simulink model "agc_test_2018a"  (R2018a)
settings: Solver=ode4  StartTime=0.0  StopTime=24  FixedStep=0.01  RelTol=1e-3

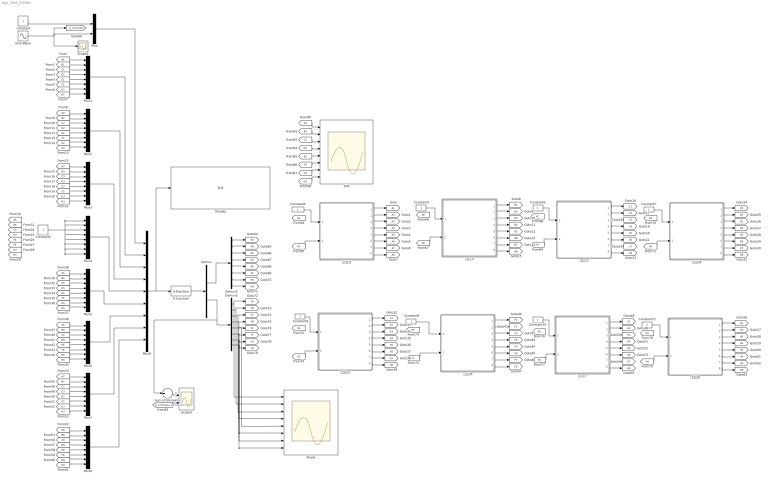
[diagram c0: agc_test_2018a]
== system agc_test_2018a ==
  Constant{,2,4..11} (10 alike) : Constant
  Demux : Demux  Outputs=2
  Demux1 : Demux  Outputs=8
  Demux2 : Demux  Outputs=8
  Display : Display
  Mux : Mux  Inputs=2
  Mux{1..8} (8 alike) : Mux  Inputs=8
  Mux9 : Mux  Inputs=9
  Power : Scope  NumInputPorts=8
  S-Function : S-Function  FunctionName=modbusCom1  SFunctionDeploymentMode=off  EnableBusSupport=off
  SOC : Scope  NumInputPorts=8
  Scope2 : Scope
  Scope3 : Scope  NumInputPorts=2
  Sine Wave : Sin  Amplitude=10000  Frequency=2*pi/8  SampleTime=0
  Sum of Elements : Sum  Inputs=+
  储能电池1 : Subsystem
  储能电池2 : Subsystem
  储能电池3 : Subsystem
  储能电池4 : Subsystem
  储能电池5 : Subsystem
  储能电池6 : Subsystem
  储能电池7 : Subsystem
  储能电池8 : Subsystem
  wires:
  Constant/1 -> Mux/1
  储能电池1/1(充放电总里程) -> [A1]
  储能电池1/2(SOC) -> [A2]
  储能电池1/3(实际功率) -> [A3]
  储能电池1/4(工作状态) -> [A4]
  储能电池1/5(额定里程) -> [A5]
  储能电池1/6(额定容量) -> [A6]
  储能电池1/7(最大充电功率) -> [A7]
  储能电池1/8(最大放电功率) -> [A8]
  储能电池2/8(最大放电功率) -> [B8]
  储能电池2/4(工作状态) -> [B4]
  储能电池2/3(实际功率) -> [B3]
  储能电池2/6(额定容量) -> [B6]
  储能电池2/1(充放电总里程) -> [B1]
  储能电池2/5(额定里程) -> [B5]
  储能电池2/2(SOC) -> [B2]
  储能电池2/7(最大充电功率) -> [B7]
  储能电池3/8(最大放电功率) -> [C8]
  储能电池3/4(工作状态) -> [C4]
  储能电池3/3(实际功率) -> [C3]
  储能电池3/6(额定容量) -> [C6]
  储能电池3/1(充放电总里程) -> [C1]
  储能电池3/5(额定里程) -> [C5]
  储能电池3/2(SOC) -> [C2]
  储能电池3/7(最大充电功率) -> [C7]
  储能电池4/8(最大放电功率) -> [D8]
  储能电池4/4(工作状态) -> [D4]
  储能电池4/3(实际功率) -> [D3]
  储能电池4/6(额定容量) -> [D6]
  储能电池4/1(充放电总里程) -> [D1]
  储能电池4/5(额定里程) -> [D5]
  储能电池4/2(SOC) -> [D2]
  储能电池4/7(最大充电功率) -> [D7]
  储能电池5/8(最大放电功率) -> [E8]
  储能电池5/4(工作状态) -> [E4]
  储能电池5/3(实际功率) -> [E3]
  储能电池5/6(额定容量) -> [E6]
  储能电池5/1(充放电总里程) -> [E1]
  储能电池5/5(额定里程) -> [E5]
  储能电池5/2(SOC) -> [E2]
  储能电池5/7(最大充电功率) -> [E7]
  储能电池6/8(最大放电功率) -> [F8]
  储能电池6/4(工作状态) -> [F4]
  储能电池6/3(实际功率) -> [F3]
  储能电池6/6(额定容量) -> [F6]
  储能电池6/1(充放电总里程) -> [F1]
  储能电池6/5(额定里程) -> [F5]
  储能电池6/2(SOC) -> [F2]
  储能电池6/7(最大充电功率) -> [F7]
  储能电池7/8(最大放电功率) -> [G8]
  储能电池7/4(工作状态) -> [G4]
  储能电池7/3(实际功率) -> [G3]
  储能电池7/6(额定容量) -> [G6]
  储能电池7/1(充放电总里程) -> [G1]
  储能电池7/5(额定里程) -> [G5]
  储能电池7/2(SOC) -> [G2]
  储能电池7/7(最大充电功率) -> [G7]
  储能电池8/8(最大放电功率) -> [H8]
  储能电池8/4(工作状态) -> [H4]
  储能电池8/3(实际功率) -> [H3]
  储能电池8/6(额定容量) -> [H6]
  储能电池8/1(充放电总里程) -> [H1]
  储能电池8/5(额定里程) -> [H5]
  储能电池8/2(SOC) -> [H2]
  储能电池8/7(最大充电功率) -> [H7]
  [A1] -> Mux1/1
  [B1] -> Mux1/2
  [C1] -> Mux1/3
  [D1] -> Mux1/4
  [E1] -> Mux1/5
  [F1] -> Mux1/6
  [G1] -> Mux1/7
  [H1] -> Mux1/8
  [G2] -> Mux2/7
  [F2] -> Mux2/6
  [D2] -> Mux2/4
  [C2] -> Mux2/3
  [B2] -> Mux2/2
  [E2] -> Mux2/5
  [H2] -> Mux2/8
  [A2] -> Mux2/1
  [B3] -> Mux3/2
  [D3] -> Mux3/4
  [F3] -> Mux3/6
  [E3] -> Mux3/5
  [H3] -> Mux3/8
  [A3] -> Mux3/1
  [G3] -> Mux3/7
  [C3] -> Mux3/3
  [D5] -> Mux5/4
  [B5] -> Mux5/2
  [A5] -> Mux5/1
  [H5] -> Mux5/8
  [E5] -> Mux5/5
  [F5] -> Mux5/6
  [G5] -> Mux5/7
  [C5] -> Mux5/3
  [G6] -> Mux6/7
  [C6] -> Mux6/3
  [F6] -> Mux6/6
  [H6] -> Mux6/8
  [E6] -> Mux6/5
  [D6] -> Mux6/4
  [B6] -> Mux6/2
  [A6] -> Mux6/1
  [A7] -> Mux7/1
  [H7] -> Mux7/8
  [E7] -> Mux7/5
  [F7] -> Mux7/6
  [B7] -> Mux7/2
  [C7] -> Mux7/3
  [D7] -> Mux7/4
  [G7] -> Mux7/7
  [H8] -> Mux8/8
  [B8] -> Mux8/2
  [A8] -> Mux8/1
  [C8] -> Mux8/3
  [F8] -> Mux8/6
  [G8] -> Mux8/7
  [E8] -> Mux8/5
  [D8] -> Mux8/4
  Mux9/1 -> Display/1, S-Function/1
  Mux/1 -> Mux9/1
  Mux1/1 -> Mux9/2
  Mux2/1 -> Mux9/3
  Mux3/1 -> Mux9/4
  Mux4/1 -> Mux9/5
  Mux5/1 -> Mux9/6
  Mux6/1 -> Mux9/7
  Mux7/1 -> Mux9/8
  Mux8/1 -> Mux9/9
  S-Function/1 -> Demux/1
  Demux/1 -> Demux1/1
  Demux/2 -> Sum of Elements/1, Demux2/1
  Demux1/8 -> [XH]
  Demux1/4 -> [XD]
  Demux1/3 -> [XC]
  Demux1/6 -> [XF]
  Demux1/1 -> [XA]
  Demux1/5 -> [XE]
  Demux1/2 -> [XB]
  Demux1/7 -> [XG]
  Demux2/7 -> Power/7, [YG]
  Demux2/1 -> Power/1, [YA]
  Demux2/2 -> Power/2, [YB]
  Demux2/6 -> Power/6, [YF]
  Demux2/8 -> Power/8, [YH]
  Demux2/5 -> Power/5, [YE]
  Demux2/4 -> Power/4, [YD]
  Demux2/3 -> Power/3, [YC]
  [YA] -> 储能电池1/2(下发给BAMS的遥调)
  [YB] -> 储能电池2/2(下发给BAMS的遥调)
  [YC] -> 储能电池3/2(下发给BAMS的遥调)
  [YD] -> 储能电池4/2(下发给BAMS的遥调)
  [YE] -> 储能电池5/2(下发给BAMS的遥调)
  [YF] -> 储能电池6/2(下发给BAMS的遥调)
  [YG] -> 储能电池7/2(下发给BAMS的遥调)
  [YH] -> 储能电池8/2(下发给BAMS的遥调)
  [C2] -> SOC/3
  [B2] -> SOC/2
  [A2] -> SOC/1
  Constant2/1 -> Mux4/6, Mux4/7, Mux4/8, Mux4/5, Mux4/4, Mux4/3, Mux4/2, Mux4/1
  Sine Wave/1 -> Scope2/1, [p_command], Mux/2
  Constant4/1 -> 储能电池1/1(下发给PMS的遥控)
  Constant5/1 -> 储能电池2/1(下发给PMS的遥控)
  Constant6/1 -> 储能电池3/1(下发给PMS的遥控)
  Constant7/1 -> 储能电池4/1(下发给PMS的遥控)
  Constant8/1 -> 储能电池5/1(下发给PMS的遥控)
  Constant9/1 -> 储能电池6/1(下发给PMS的遥控)
  Constant10/1 -> 储能电池7/1(下发给PMS的遥控)
  Constant11/1 -> 储能电池8/1(下发给PMS的遥控)
  Sum of Elements/1 -> Scope3/1  "p"
  [p_command] -> Scope3/2  "command"
  [D2] -> SOC/4
  [E2] -> SOC/5
  [F2] -> SOC/6
  [G2] -> SOC/7
  [H2] -> SOC/8

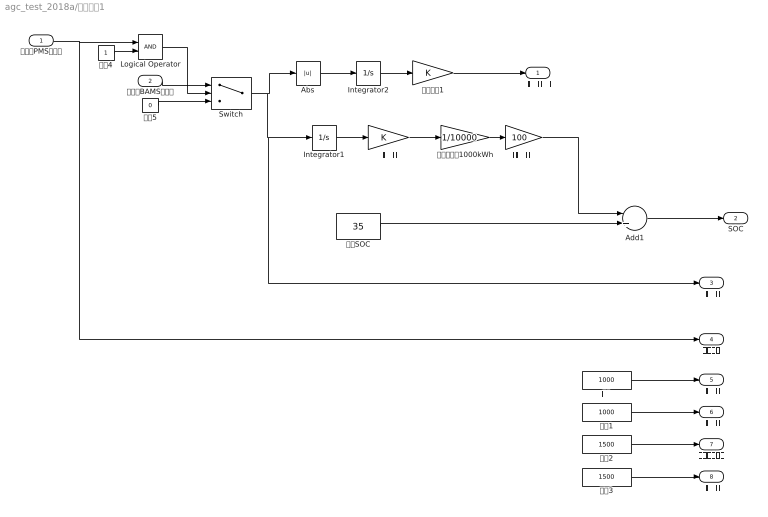
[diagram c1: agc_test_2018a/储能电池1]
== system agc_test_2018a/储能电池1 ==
  下发给PMS的遥控 : Inport
  下发给BAMS的遥调 : Inport  Port=2
  Abs : Abs
  Add1 : Sum  Inputs=-+
  Integrator1 : Integrator
  Integrator2 : Integrator
  Logical Operator : Logic  AllPortsSameDT=off  OutDataTypeStr=boolean
  Switch : Switch  Criteria=u2 ~= 0
  初始SOC : Constant  Value=35
  常数 : Constant  Value=1000
  常数1 : Constant  Value=1000
  常数2 : Constant  Value=1500
  常数3 : Constant  Value=1500
  常数4 : Constant
  常数5 : Constant  Value=0
  百分比转化 : Gain  Gain=100
  秒转为时 : Gain
  秒转为时1 : Gain
  蓄电池容量1000kWh : Gain  Gain=1/10000
  充放电总里程 : Outport
  SOC : Outport  Port=2
  实际功率 : Outport  Port=3
  工作状态 : Outport  Port=4
  额定里程 : Outport  Port=5
  额定容量 : Outport  Port=6
  最大充电功率 : Outport  Port=7
  最大放电功率 : Outport  Port=8
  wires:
  初始SOC/1 -> Add1/2
  下发给BAMS的遥调/1 -> Switch/1
  蓄电池容量1000kWh/1 -> 百分比转化/1
  百分比转化/1 -> Add1/1
  Add1/1 -> SOC/1
  Abs/1 -> Integrator2/1
  Integrator1/1 -> 秒转为时/1
  秒转为时/1 -> 蓄电池容量1000kWh/1
  Integrator2/1 -> 秒转为时1/1
  秒转为时1/1 -> 充放电总里程/1
  下发给PMS的遥控/1 -> Logical Operator/1, 工作状态/1
  常数/1 -> 额定里程/1
  常数1/1 -> 额定容量/1
  常数2/1 -> 最大充电功率/1
  常数3/1 -> 最大放电功率/1
  常数4/1 -> Logical Operator/2
  Logical Operator/1 -> Switch/2
  常数5/1 -> Switch/3
  Switch/1 -> 实际功率/1, Integrator1/1, Abs/1

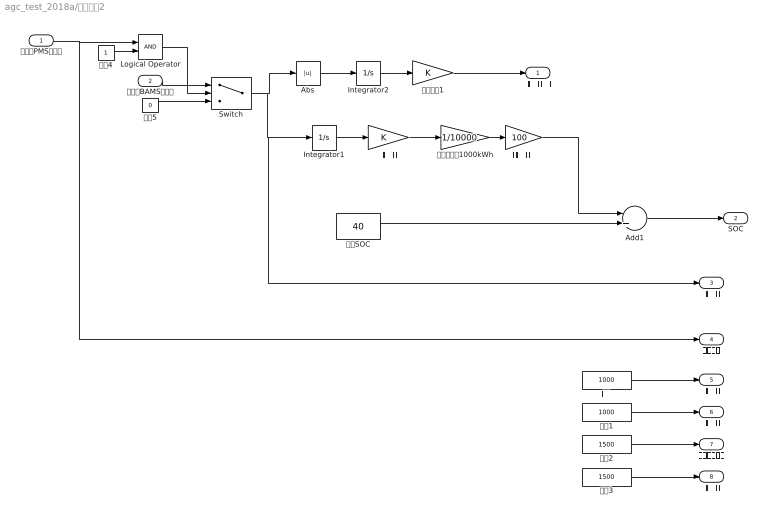
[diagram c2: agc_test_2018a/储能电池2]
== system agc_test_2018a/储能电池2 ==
  下发给PMS的遥控 : Inport
  下发给BAMS的遥调 : Inport  Port=2
  Abs : Abs
  Add1 : Sum  Inputs=-+
  Integrator1 : Integrator
  Integrator2 : Integrator
  Logical Operator : Logic  AllPortsSameDT=off  OutDataTypeStr=boolean
  Switch : Switch  Criteria=u2 ~= 0
  初始SOC : Constant  Value=40
  常数 : Constant  Value=1000
  常数1 : Constant  Value=1000
  常数2 : Constant  Value=1500
  常数3 : Constant  Value=1500
  常数4 : Constant
  常数5 : Constant  Value=0
  百分比转化 : Gain  Gain=100
  秒转为时 : Gain
  秒转为时1 : Gain
  蓄电池容量1000kWh : Gain  Gain=1/10000
  充放电总里程 : Outport
  SOC : Outport  Port=2
  实际功率 : Outport  Port=3
  工作状态 : Outport  Port=4
  额定里程 : Outport  Port=5
  额定容量 : Outport  Port=6
  最大充电功率 : Outport  Port=7
  最大放电功率 : Outport  Port=8
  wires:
  初始SOC/1 -> Add1/2
  下发给BAMS的遥调/1 -> Switch/1
  蓄电池容量1000kWh/1 -> 百分比转化/1
  百分比转化/1 -> Add1/1
  Add1/1 -> SOC/1
  Abs/1 -> Integrator2/1
  Integrator1/1 -> 秒转为时/1
  秒转为时/1 -> 蓄电池容量1000kWh/1
  Integrator2/1 -> 秒转为时1/1
  秒转为时1/1 -> 充放电总里程/1
  下发给PMS的遥控/1 -> Logical Operator/1, 工作状态/1
  常数/1 -> 额定里程/1
  常数1/1 -> 额定容量/1
  常数2/1 -> 最大充电功率/1
  常数3/1 -> 最大放电功率/1
  常数4/1 -> Logical Operator/2
  Logical Operator/1 -> Switch/2
  常数5/1 -> Switch/3
  Switch/1 -> 实际功率/1, Integrator1/1, Abs/1

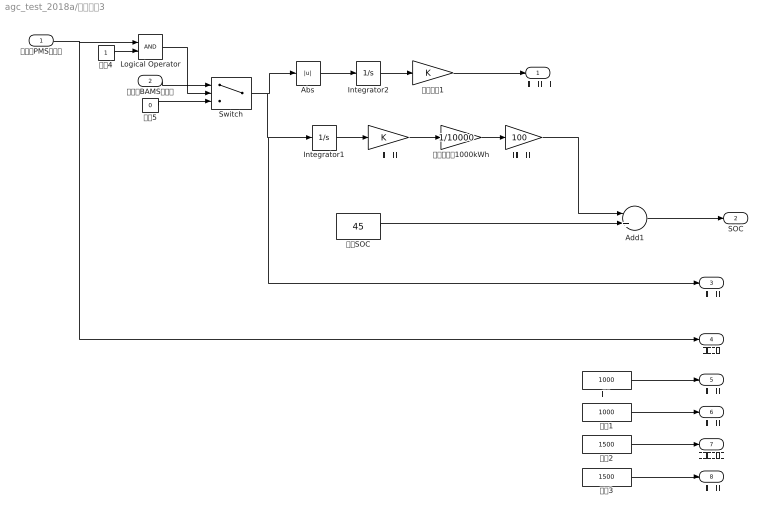
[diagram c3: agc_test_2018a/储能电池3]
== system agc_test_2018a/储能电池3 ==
  下发给PMS的遥控 : Inport
  下发给BAMS的遥调 : Inport  Port=2
  Abs : Abs
  Add1 : Sum  Inputs=-+
  Integrator1 : Integrator
  Integrator2 : Integrator
  Logical Operator : Logic  AllPortsSameDT=off  OutDataTypeStr=boolean
  Switch : Switch  Criteria=u2 ~= 0
  初始SOC : Constant  Value=45
  常数 : Constant  Value=1000
  常数1 : Constant  Value=1000
  常数2 : Constant  Value=1500
  常数3 : Constant  Value=1500
  常数4 : Constant
  常数5 : Constant  Value=0
  百分比转化 : Gain  Gain=100
  秒转为时 : Gain
  秒转为时1 : Gain
  蓄电池容量1000kWh : Gain  Gain=1/10000
  充放电总里程 : Outport
  SOC : Outport  Port=2
  实际功率 : Outport  Port=3
  工作状态 : Outport  Port=4
  额定里程 : Outport  Port=5
  额定容量 : Outport  Port=6
  最大充电功率 : Outport  Port=7
  最大放电功率 : Outport  Port=8
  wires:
  初始SOC/1 -> Add1/2
  下发给BAMS的遥调/1 -> Switch/1
  蓄电池容量1000kWh/1 -> 百分比转化/1
  百分比转化/1 -> Add1/1
  Add1/1 -> SOC/1
  Abs/1 -> Integrator2/1
  Integrator1/1 -> 秒转为时/1
  秒转为时/1 -> 蓄电池容量1000kWh/1
  Integrator2/1 -> 秒转为时1/1
  秒转为时1/1 -> 充放电总里程/1
  下发给PMS的遥控/1 -> Logical Operator/1, 工作状态/1
  常数/1 -> 额定里程/1
  常数1/1 -> 额定容量/1
  常数2/1 -> 最大充电功率/1
  常数3/1 -> 最大放电功率/1
  常数4/1 -> Logical Operator/2
  Logical Operator/1 -> Switch/2
  常数5/1 -> Switch/3
  Switch/1 -> 实际功率/1, Integrator1/1, Abs/1

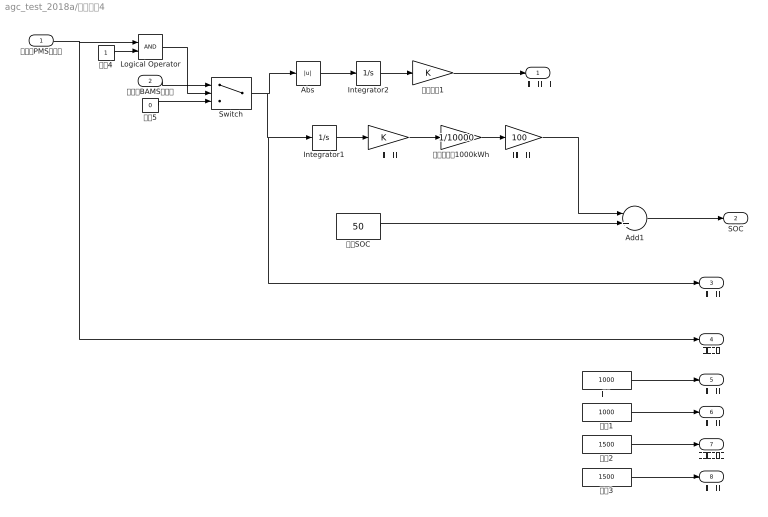
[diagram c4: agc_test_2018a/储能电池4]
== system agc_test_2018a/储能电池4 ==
  下发给PMS的遥控 : Inport
  下发给BAMS的遥调 : Inport  Port=2
  Abs : Abs
  Add1 : Sum  Inputs=-+
  Integrator1 : Integrator
  Integrator2 : Integrator
  Logical Operator : Logic  AllPortsSameDT=off  OutDataTypeStr=boolean
  Switch : Switch  Criteria=u2 ~= 0
  初始SOC : Constant  Value=50
  常数 : Constant  Value=1000
  常数1 : Constant  Value=1000
  常数2 : Constant  Value=1500
  常数3 : Constant  Value=1500
  常数4 : Constant
  常数5 : Constant  Value=0
  百分比转化 : Gain  Gain=100
  秒转为时 : Gain
  秒转为时1 : Gain
  蓄电池容量1000kWh : Gain  Gain=1/10000
  充放电总里程 : Outport
  SOC : Outport  Port=2
  实际功率 : Outport  Port=3
  工作状态 : Outport  Port=4
  额定里程 : Outport  Port=5
  额定容量 : Outport  Port=6
  最大充电功率 : Outport  Port=7
  最大放电功率 : Outport  Port=8
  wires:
  初始SOC/1 -> Add1/2
  下发给BAMS的遥调/1 -> Switch/1
  蓄电池容量1000kWh/1 -> 百分比转化/1
  百分比转化/1 -> Add1/1
  Add1/1 -> SOC/1
  Abs/1 -> Integrator2/1
  Integrator1/1 -> 秒转为时/1
  秒转为时/1 -> 蓄电池容量1000kWh/1
  Integrator2/1 -> 秒转为时1/1
  秒转为时1/1 -> 充放电总里程/1
  下发给PMS的遥控/1 -> Logical Operator/1, 工作状态/1
  常数/1 -> 额定里程/1
  常数1/1 -> 额定容量/1
  常数2/1 -> 最大充电功率/1
  常数3/1 -> 最大放电功率/1
  常数4/1 -> Logical Operator/2
  Logical Operator/1 -> Switch/2
  常数5/1 -> Switch/3
  Switch/1 -> 实际功率/1, Integrator1/1, Abs/1

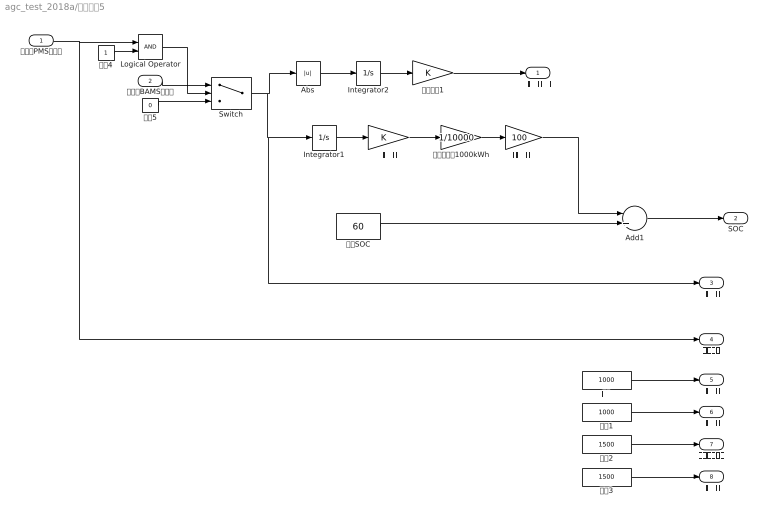
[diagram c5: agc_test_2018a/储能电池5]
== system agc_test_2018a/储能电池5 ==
  下发给PMS的遥控 : Inport
  下发给BAMS的遥调 : Inport  Port=2
  Abs : Abs
  Add1 : Sum  Inputs=-+
  Integrator1 : Integrator
  Integrator2 : Integrator
  Logical Operator : Logic  AllPortsSameDT=off  OutDataTypeStr=boolean
  Switch : Switch  Criteria=u2 ~= 0
  初始SOC : Constant  Value=60
  常数 : Constant  Value=1000
  常数1 : Constant  Value=1000
  常数2 : Constant  Value=1500
  常数3 : Constant  Value=1500
  常数4 : Constant
  常数5 : Constant  Value=0
  百分比转化 : Gain  Gain=100
  秒转为时 : Gain
  秒转为时1 : Gain
  蓄电池容量1000kWh : Gain  Gain=1/10000
  充放电总里程 : Outport
  SOC : Outport  Port=2
  实际功率 : Outport  Port=3
  工作状态 : Outport  Port=4
  额定里程 : Outport  Port=5
  额定容量 : Outport  Port=6
  最大充电功率 : Outport  Port=7
  最大放电功率 : Outport  Port=8
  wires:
  初始SOC/1 -> Add1/2
  下发给BAMS的遥调/1 -> Switch/1
  蓄电池容量1000kWh/1 -> 百分比转化/1
  百分比转化/1 -> Add1/1
  Add1/1 -> SOC/1
  Abs/1 -> Integrator2/1
  Integrator1/1 -> 秒转为时/1
  秒转为时/1 -> 蓄电池容量1000kWh/1
  Integrator2/1 -> 秒转为时1/1
  秒转为时1/1 -> 充放电总里程/1
  下发给PMS的遥控/1 -> Logical Operator/1, 工作状态/1
  常数/1 -> 额定里程/1
  常数1/1 -> 额定容量/1
  常数2/1 -> 最大充电功率/1
  常数3/1 -> 最大放电功率/1
  常数4/1 -> Logical Operator/2
  Logical Operator/1 -> Switch/2
  常数5/1 -> Switch/3
  Switch/1 -> 实际功率/1, Integrator1/1, Abs/1

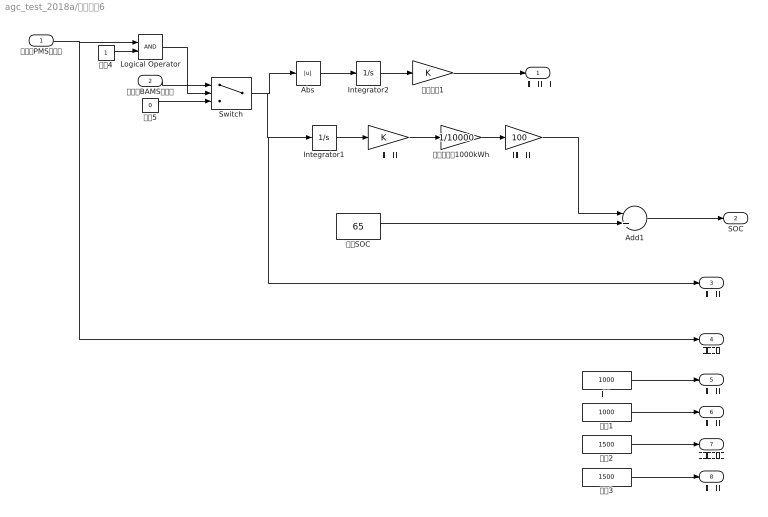
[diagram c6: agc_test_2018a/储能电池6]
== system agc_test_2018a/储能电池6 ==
  下发给PMS的遥控 : Inport
  下发给BAMS的遥调 : Inport  Port=2
  Abs : Abs
  Add1 : Sum  Inputs=-+
  Integrator1 : Integrator
  Integrator2 : Integrator
  Logical Operator : Logic  AllPortsSameDT=off  OutDataTypeStr=boolean
  Switch : Switch  Criteria=u2 ~= 0
  初始SOC : Constant  Value=65
  常数 : Constant  Value=1000
  常数1 : Constant  Value=1000
  常数2 : Constant  Value=1500
  常数3 : Constant  Value=1500
  常数4 : Constant
  常数5 : Constant  Value=0
  百分比转化 : Gain  Gain=100
  秒转为时 : Gain
  秒转为时1 : Gain
  蓄电池容量1000kWh : Gain  Gain=1/10000
  充放电总里程 : Outport
  SOC : Outport  Port=2
  实际功率 : Outport  Port=3
  工作状态 : Outport  Port=4
  额定里程 : Outport  Port=5
  额定容量 : Outport  Port=6
  最大充电功率 : Outport  Port=7
  最大放电功率 : Outport  Port=8
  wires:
  初始SOC/1 -> Add1/2
  下发给BAMS的遥调/1 -> Switch/1
  蓄电池容量1000kWh/1 -> 百分比转化/1
  百分比转化/1 -> Add1/1
  Add1/1 -> SOC/1
  Abs/1 -> Integrator2/1
  Integrator1/1 -> 秒转为时/1
  秒转为时/1 -> 蓄电池容量1000kWh/1
  Integrator2/1 -> 秒转为时1/1
  秒转为时1/1 -> 充放电总里程/1
  下发给PMS的遥控/1 -> Logical Operator/1, 工作状态/1
  常数/1 -> 额定里程/1
  常数1/1 -> 额定容量/1
  常数2/1 -> 最大充电功率/1
  常数3/1 -> 最大放电功率/1
  常数4/1 -> Logical Operator/2
  Logical Operator/1 -> Switch/2
  常数5/1 -> Switch/3
  Switch/1 -> 实际功率/1, Integrator1/1, Abs/1

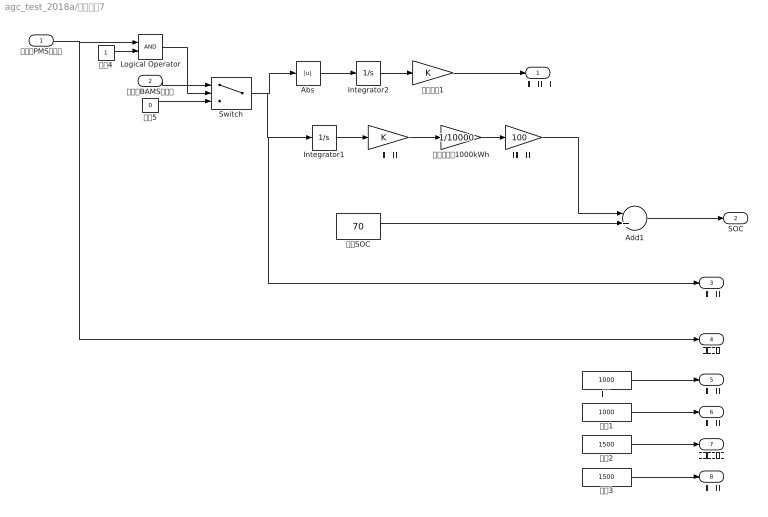
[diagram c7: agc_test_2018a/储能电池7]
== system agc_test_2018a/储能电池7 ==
  下发给PMS的遥控 : Inport
  下发给BAMS的遥调 : Inport  Port=2
  Abs : Abs
  Add1 : Sum  Inputs=-+
  Integrator1 : Integrator
  Integrator2 : Integrator
  Logical Operator : Logic  AllPortsSameDT=off  OutDataTypeStr=boolean
  Switch : Switch  Criteria=u2 ~= 0
  初始SOC : Constant  Value=70
  常数 : Constant  Value=1000
  常数1 : Constant  Value=1000
  常数2 : Constant  Value=1500
  常数3 : Constant  Value=1500
  常数4 : Constant
  常数5 : Constant  Value=0
  百分比转化 : Gain  Gain=100
  秒转为时 : Gain
  秒转为时1 : Gain
  蓄电池容量1000kWh : Gain  Gain=1/10000
  充放电总里程 : Outport
  SOC : Outport  Port=2
  实际功率 : Outport  Port=3
  工作状态 : Outport  Port=4
  额定里程 : Outport  Port=5
  额定容量 : Outport  Port=6
  最大充电功率 : Outport  Port=7
  最大放电功率 : Outport  Port=8
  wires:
  初始SOC/1 -> Add1/2
  下发给BAMS的遥调/1 -> Switch/1
  蓄电池容量1000kWh/1 -> 百分比转化/1
  百分比转化/1 -> Add1/1
  Add1/1 -> SOC/1
  Abs/1 -> Integrator2/1
  Integrator1/1 -> 秒转为时/1
  秒转为时/1 -> 蓄电池容量1000kWh/1
  Integrator2/1 -> 秒转为时1/1
  秒转为时1/1 -> 充放电总里程/1
  下发给PMS的遥控/1 -> Logical Operator/1, 工作状态/1
  常数/1 -> 额定里程/1
  常数1/1 -> 额定容量/1
  常数2/1 -> 最大充电功率/1
  常数3/1 -> 最大放电功率/1
  常数4/1 -> Logical Operator/2
  Logical Operator/1 -> Switch/2
  常数5/1 -> Switch/3
  Switch/1 -> 实际功率/1, Integrator1/1, Abs/1

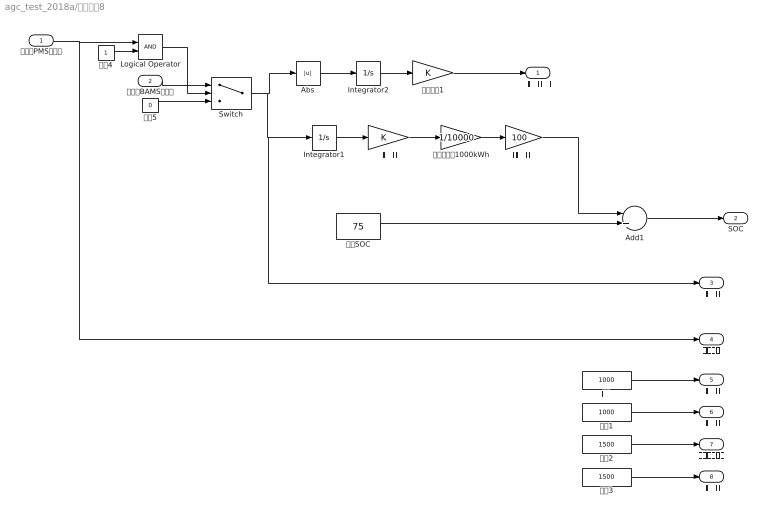
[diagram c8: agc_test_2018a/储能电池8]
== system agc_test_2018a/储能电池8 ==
  下发给PMS的遥控 : Inport
  下发给BAMS的遥调 : Inport  Port=2
  Abs : Abs
  Add1 : Sum  Inputs=-+
  Integrator1 : Integrator
  Integrator2 : Integrator
  Logical Operator : Logic  AllPortsSameDT=off  OutDataTypeStr=boolean
  Switch : Switch  Criteria=u2 ~= 0
  初始SOC : Constant  Value=75
  常数 : Constant  Value=1000
  常数1 : Constant  Value=1000
  常数2 : Constant  Value=1500
  常数3 : Constant  Value=1500
  常数4 : Constant
  常数5 : Constant  Value=0
  百分比转化 : Gain  Gain=100
  秒转为时 : Gain
  秒转为时1 : Gain
  蓄电池容量1000kWh : Gain  Gain=1/10000
  充放电总里程 : Outport
  SOC : Outport  Port=2
  实际功率 : Outport  Port=3
  工作状态 : Outport  Port=4
  额定里程 : Outport  Port=5
  额定容量 : Outport  Port=6
  最大充电功率 : Outport  Port=7
  最大放电功率 : Outport  Port=8
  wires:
  初始SOC/1 -> Add1/2
  下发给BAMS的遥调/1 -> Switch/1
  蓄电池容量1000kWh/1 -> 百分比转化/1
  百分比转化/1 -> Add1/1
  Add1/1 -> SOC/1
  Abs/1 -> Integrator2/1
  Integrator1/1 -> 秒转为时/1
  秒转为时/1 -> 蓄电池容量1000kWh/1
  Integrator2/1 -> 秒转为时1/1
  秒转为时1/1 -> 充放电总里程/1
  下发给PMS的遥控/1 -> Logical Operator/1, 工作状态/1
  常数/1 -> 额定里程/1
  常数1/1 -> 额定容量/1
  常数2/1 -> 最大充电功率/1
  常数3/1 -> 最大放电功率/1
  常数4/1 -> Logical Operator/2
  Logical Operator/1 -> Switch/2
  常数5/1 -> Switch/3
  Switch/1 -> 实际功率/1, Integrator1/1, Abs/1
